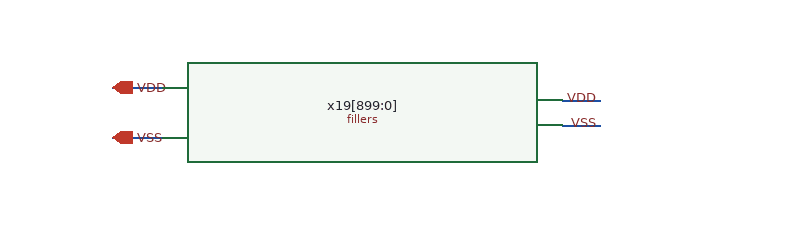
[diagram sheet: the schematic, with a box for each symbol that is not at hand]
v {xschem version=3.4.8RC file_version=1.3}
G {}
K {}
V {}
S {}
F {}
E {}
N -60 -120 -20 -120 {lab=VDD}
N -60 -80 -20 -80 {lab=VSS}
N 300 -90 330 -90 {lab=VSS}
N 300 -110 330 -110 {lab=VDD}
C {iopin.sym} -60 -120 0 1 {name=p46 lab=VDD}
C {iopin.sym} -60 -80 0 1 {name=p47 lab=VSS}
C {fillers.sym} 150 -100 0 0 {name=x19[899:0]}
C {lab_wire.sym} 330 -110 0 0 {name=p97 sig_type=std_logic lab=VDD
}
C {lab_wire.sym} 330 -90 0 0 {name=p99 sig_type=std_logic lab=VSS
}
